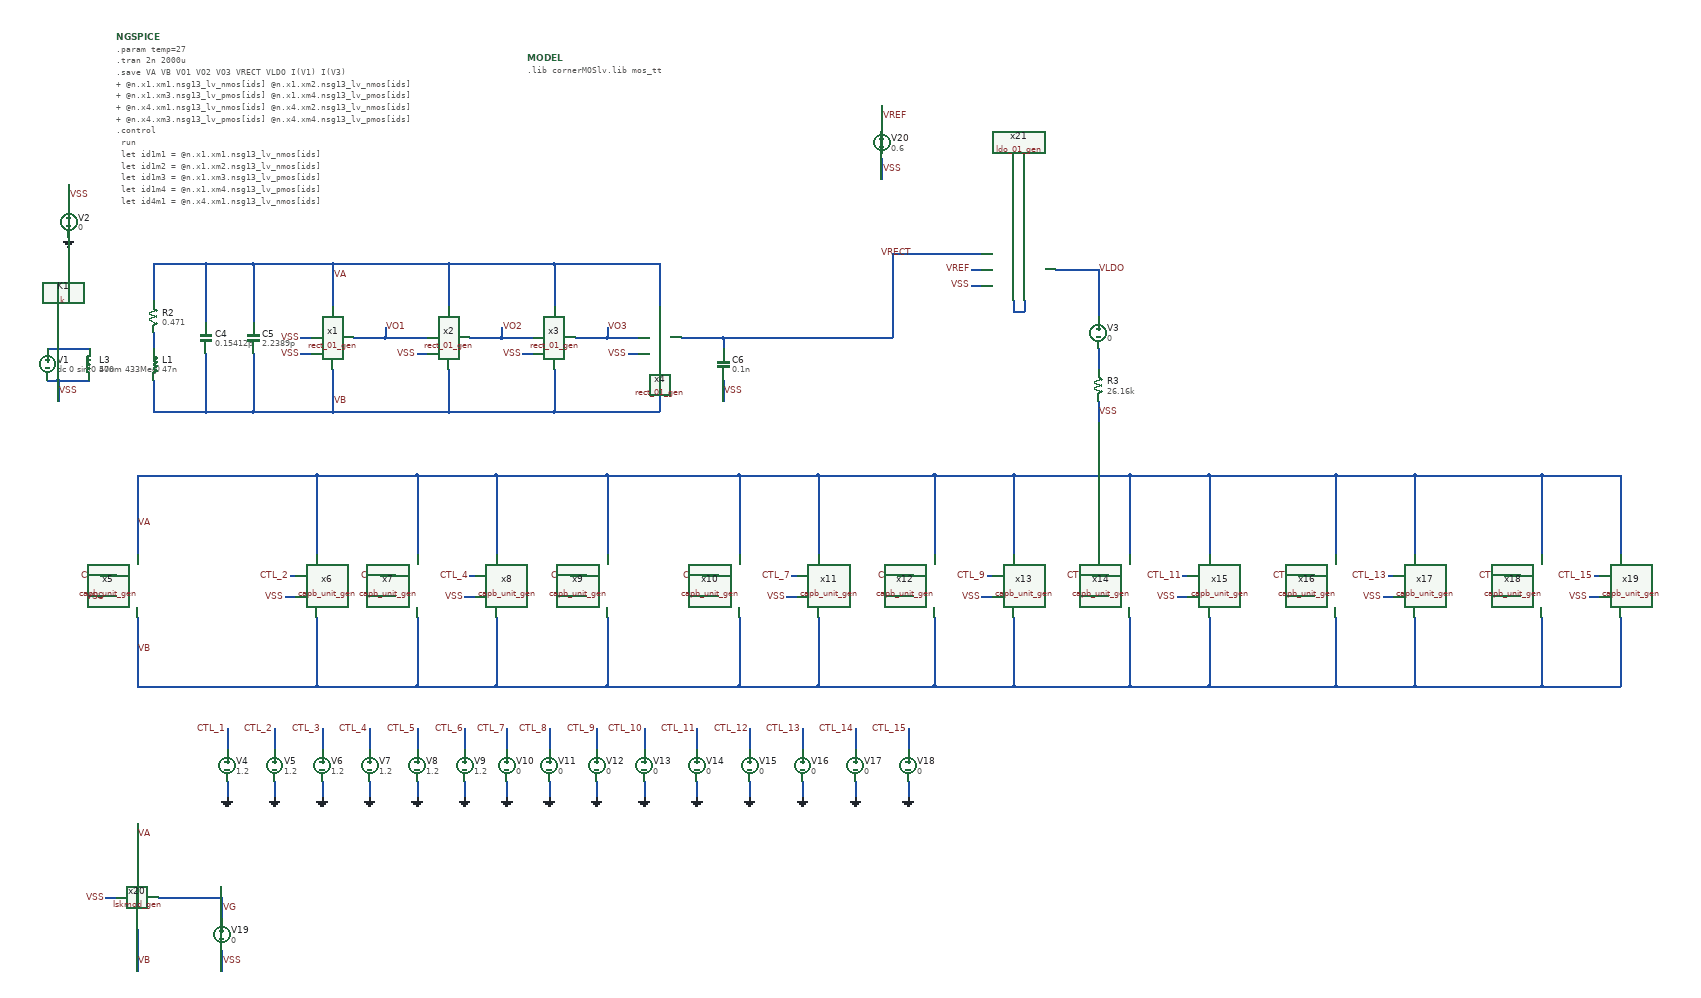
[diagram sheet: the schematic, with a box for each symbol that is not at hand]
v {xschem version=3.4.6 file_version=1.2}
G {}
K {}
V {}
S {}
E {}
N 40 -530 40 -490 {lab=VSS}
N 640 -240 720 -240 {lab=VO1}
N 480 -240 500 -240 {lab=VSS}
N 540 -380 540 -300 {lab=VA}
N 390 -380 540 -380 {lab=VA}
N 390 -100 540 -100 {lab=VB}
N 860 -240 920 -240 {lab=VO2}
N 1060 -240 1120 -240 {lab=VO3}
N 1280 -240 1280 -220 {lab=VRECT}
N 1280 -160 1280 -120 {lab=VSS}
N 1200 -240 1280 -240 {lab=VRECT}
N 1160 -180 1160 -100 {lab=VB}
N 1160 -380 1160 -300 {lab=VA}
N 960 -100 1160 -100 {lab=VB}
N 960 -380 1160 -380 {lab=VA}
N 960 -180 960 -100 {lab=VB}
N 960 -380 960 -300 {lab=VA}
N 760 -100 960 -100 {lab=VB}
N 760 -380 960 -380 {lab=VA}
N 760 -180 760 -100 {lab=VB}
N 760 -380 760 -300 {lab=VA}
N 540 -100 760 -100 {lab=VB}
N 540 -380 760 -380 {lab=VA}
N 640 -260 640 -240 {lab=VO1}
N 860 -260 860 -240 {lab=VO2}
N 800 -240 860 -240 {lab=VO2}
N 1060 -260 1060 -240 {lab=VO3}
N 1000 -240 1060 -240 {lab=VO3}
N 540 -180 540 -100 {lab=VB}
N 200 -250 200 -220 {lab=#net1}
N 200 -380 200 -310 {lab=VA}
N 300 -380 300 -270 {lab=VA}
N 390 -210 390 -100 {lab=VB}
N 390 -380 390 -270 {lab=VA}
N 580 -240 640 -240 {lab=VO1}
N 200 -160 200 -100 {lab=VB}
N 200 -380 300 -380 {lab=VA}
N 300 -380 390 -380 {lab=VA}
N 300 -210 300 -100 {lab=VB}
N 200 -100 300 -100 {lab=VB}
N 300 -100 390 -100 {lab=VB}
N 0 -220 80 -220 {lab=#net2}
N 20 -160 80 -160 {lab=VSS}
N 20 -160 20 -120 {lab=VSS}
N 0 -160 20 -160 {lab=VSS}
N 480 -210 500 -210 {lab=VSS}
N 700 -210 720 -210 {lab=VSS}
N 900 -210 920 -210 {lab=VSS}
N 1100 -210 1120 -210 {lab=VSS}
N 100 210 130 210 {lab=CTL_1}
N 460 210 470 210 {lab=CTL_2}
N 170 20 170 170 {lab=VA}
N 510 20 510 170 {lab=VA}
N 630 210 660 210 {lab=CTL_3}
N 800 210 810 210 {lab=CTL_4}
N 700 20 700 170 {lab=VA}
N 850 20 850 170 {lab=VA}
N 990 210 1020 210 {lab=CTL_5}
N 1240 210 1270 210 {lab=CTL_6}
N 1410 210 1420 210 {lab=CTL_7}
N 1610 210 1640 210 {lab=CTL_8}
N 1780 210 1790 210 {lab=CTL_9}
N 1980 210 2010 210 {lab=CTL_10}
N 2150 210 2160 210 {lab=CTL_11}
N 2200 20 2200 170 {lab=VA}
N 2370 210 2400 210 {lab=CTL_12}
N 2540 210 2550 210 {lab=CTL_13}
N 2440 20 2440 170 {lab=VA}
N 2590 20 2590 170 {lab=VA}
N 2760 210 2790 210 {lab=CTL_14}
N 2930 210 2940 210 {lab=CTL_15}
N 2830 20 2830 170 {lab=VA}
N 2980 20 2980 170 {lab=VA}
N 2830 20 2980 20 {lab=VA}
N 510 20 700 20 {lab=VA}
N 700 20 850 20 {lab=VA}
N 2200 20 2440 20 {lab=VA}
N 2440 20 2590 20 {lab=VA}
N 2590 20 2830 20 {lab=VA}
N 2830 420 2980 420 {lab=VB}
N 510 420 700 420 {lab=VB}
N 700 420 850 420 {lab=VB}
N 2050 420 2200 420 {lab=VB}
N 2200 420 2440 420 {lab=VB}
N 2440 420 2590 420 {lab=VB}
N 2590 420 2830 420 {lab=VB}
N 1830 420 2050 420 {lab=VB}
N 850 420 1060 420 {lab=VB}
N 1060 420 1310 420 {lab=VB}
N 1310 420 1460 420 {lab=VB}
N 1460 420 1680 420 {lab=VB}
N 1680 420 1830 420 {lab=VB}
N 2050 20 2200 20 {lab=VA}
N 2050 20 2050 170 {lab=VA}
N 1830 20 2050 20 {lab=VA}
N 1830 20 1830 170 {lab=VA}
N 1680 20 1830 20 {lab=VA}
N 1680 20 1680 170 {lab=VA}
N 1460 20 1680 20 {lab=VA}
N 1460 20 1460 170 {lab=VA}
N 1310 20 1460 20 {lab=VA}
N 1310 20 1310 170 {lab=VA}
N 1060 20 1310 20 {lab=VA}
N 1060 20 1060 170 {lab=VA}
N 850 20 1060 20 {lab=VA}
N 340 500 340 540 {lab=CTL_1}
N 340 600 340 630 {lab=GND}
N 430 500 430 540 {lab=CTL_2}
N 430 600 430 630 {lab=GND}
N 520 500 520 540 {lab=CTL_3}
N 520 600 520 630 {lab=GND}
N 610 500 610 540 {lab=CTL_4}
N 610 600 610 630 {lab=GND}
N 700 500 700 540 {lab=CTL_5}
N 700 600 700 630 {lab=GND}
N 790 500 790 540 {lab=CTL_6}
N 790 600 790 630 {lab=GND}
N 870 500 870 540 {lab=CTL_7}
N 870 600 870 630 {lab=GND}
N 950 500 950 540 {lab=CTL_8}
N 950 600 950 630 {lab=GND}
N 1040 500 1040 540 {lab=CTL_9}
N 1040 600 1040 630 {lab=GND}
N 1130 500 1130 540 {lab=CTL_10}
N 1130 600 1130 630 {lab=GND}
N 1230 500 1230 540 {lab=CTL_11}
N 1230 600 1230 630 {lab=GND}
N 1330 500 1330 540 {lab=CTL_12}
N 1330 600 1330 630 {lab=GND}
N 1430 500 1430 540 {lab=CTL_13}
N 1430 600 1430 630 {lab=GND}
N 1530 500 1530 540 {lab=CTL_14}
N 1530 600 1530 630 {lab=GND}
N 1630 500 1630 540 {lab=CTL_15}
N 1630 600 1630 630 {lab=GND}
N 110 250 130 250 {lab=VSS}
N 450 250 470 250 {lab=VSS}
N 640 250 660 250 {lab=VSS}
N 790 250 810 250 {lab=VSS}
N 1000 250 1020 250 {lab=VSS}
N 1250 250 1270 250 {lab=VSS}
N 1400 250 1420 250 {lab=VSS}
N 1620 250 1640 250 {lab=VSS}
N 1770 250 1790 250 {lab=VSS}
N 1990 250 2010 250 {lab=VSS}
N 2140 250 2160 250 {lab=VSS}
N 2380 250 2400 250 {lab=VSS}
N 2530 250 2550 250 {lab=VSS}
N 2770 250 2790 250 {lab=VSS}
N 2920 250 2940 250 {lab=VSS}
N 170 290 170 420 {lab=VB}
N 510 290 510 420 {lab=VB}
N 700 290 700 420 {lab=VB}
N 850 290 850 420 {lab=VB}
N 1060 290 1060 420 {lab=VB}
N 1310 290 1310 420 {lab=VB}
N 1460 290 1460 420 {lab=VB}
N 1680 290 1680 420 {lab=VB}
N 1830 290 1830 420 {lab=VB}
N 2050 290 2050 420 {lab=VB}
N 2200 290 2200 420 {lab=VB}
N 2440 290 2440 420 {lab=VB}
N 2590 290 2590 420 {lab=VB}
N 2830 290 2830 420 {lab=VB}
N 2980 290 2980 420 {lab=VB}
N 170 420 510 420 {lab=VB}
N 170 20 510 20 {lab=VA}
N 330 820 330 860 {lab=VG}
N 330 920 330 960 {lab=VSS}
N 170 680 170 760 {lab=VA}
N 170 880 170 960 {lab=VB}
N 110 820 130 820 {lab=VSS}
N 210 820 330 820 {lab=VG}
N 1580 -680 1580 -640 {lab=VREF}
N 1580 -580 1580 -540 {lab=VSS}
N 1990 -120 1990 -80 {lab=VSS}
N 1990 -370 1990 -280 {lab=VLDO}
N 1750 -370 1770 -370 {lab=VREF}
N 1910 -370 1990 -370 {lab=VLDO}
N 1850 -310 1850 -290 {lab=#net3}
N 1830 -310 1830 -290 {lab=#net3}
N 1750 -340 1770 -340 {lab=VSS}
N 1830 -290 1850 -290 {lab=#net3}
N 1280 -240 1600 -240 {lab=VRECT}
N 1600 -400 1600 -240 {lab=VRECT}
N 1600 -400 1770 -400 {lab=VRECT}
N 1990 -220 1990 -180 {lab=#net4}
C {vsource.sym} 0 -190 0 1 {name=V1 value="dc 0 sin(0 500m 433Meg)" savecurrent=false}
C {code_shown.sym} 130 -810 0 0 {name=NGSPICE only_toplevel=false value="
.param temp=27
.tran 2n 2000u
.save VA VB VO1 VO2 VO3 VRECT VLDO I(V1) I(V3)
+ @n.x1.xm1.nsg13_lv_nmos[ids] @n.x1.xm2.nsg13_lv_nmos[ids]
+ @n.x1.xm3.nsg13_lv_pmos[ids] @n.x1.xm4.nsg13_lv_pmos[ids]
+ @n.x4.xm1.nsg13_lv_nmos[ids] @n.x4.xm2.nsg13_lv_nmos[ids]
+ @n.x4.xm3.nsg13_lv_pmos[ids] @n.x4.xm4.nsg13_lv_pmos[ids]

.control
  run
  let id1m1 = @n.x1.xm1.nsg13_lv_nmos[ids]
  let id1m2 = @n.x1.xm2.nsg13_lv_nmos[ids]
  let id1m3 = @n.x1.xm3.nsg13_lv_pmos[ids]
  let id1m4 = @n.x1.xm4.nsg13_lv_pmos[ids]
  let id4m1 = @n.x4.xm1.nsg13_lv_nmos[ids]
  let id4m2 = @n.x4.xm2.nsg13_lv_nmos[ids]
  let id4m3 = @n.x4.xm3.nsg13_lv_pmos[ids]
  let id4m4 = @n.x4.xm4.nsg13_lv_pmos[ids]
  set filetype=ascii
  write tb_wpdt_g1.raw v(VA) v(VB) v(VO1) v(VO2) v(VO3) v(VRECT) v(VLDO) I(V1) I(V3) id1m1 id1m2 id1m3 id1m4 id4m1 id4m2 id4m3 id4m4
.endc
"}
C {vsource.sym} 40 -460 0 0 {name=V2 value=0 savecurrent=false}
C {gnd.sym} 40 -430 0 0 {name=l2 lab=GND}
C {lab_pin.sym} 40 -510 0 1 {name=p2 sig_type=std_logic lab=VSS}
C {code_shown.sym} 910 -770 0 0 {name=MODEL only_toplevel=false value="
.lib cornerMOSlv.lib mos_tt
"}
C {lab_pin.sym} 480 -240 0 0 {name=p9 sig_type=std_logic lab=VSS}
C {lab_pin.sym} 540 -360 0 1 {name=p1 sig_type=std_logic lab=VA}
C {lab_pin.sym} 540 -120 0 1 {name=p3 sig_type=std_logic lab=VB}
C {rect_01_gen.sym} 540 -240 0 0 {name=x1
Ls=47e-9
Rs=0.471
f_sr=1870e6
q_coil=289
f_op=433e6
Vrect=1.6
Vrfpeak=0.5
Isys=80e-6
schematic="rect_unit.py(@Ls\\,@Rs\\,@f_sr\\,@q_coil\\,@f_op\\,@Vrect\\,@Vrfpeak\\,@Isys\\)"
tclcommand="edit_file [abs_sym_path rect_unit.py]"}
C {capa.sym} 1280 -190 0 0 {name=C6
m=1
value=0.1n
footprint=1206
device="ceramic capacitor"}
C {lab_pin.sym} 1280 -140 0 1 {name=p12 sig_type=std_logic lab=VSS}
C {lab_pin.sym} 640 -260 0 1 {name=p13 sig_type=std_logic lab=VO1}
C {lab_pin.sym} 860 -260 0 1 {name=p14 sig_type=std_logic lab=VO2}
C {lab_pin.sym} 1060 -260 0 1 {name=p15 sig_type=std_logic lab=VO3}
C {vsource.sym} 1990 -250 0 0 {name=V3 value=0 savecurrent=false}
C {ind.sym} 200 -190 0 0 {name=L1
m=1
value=47n
footprint=1206
device=inductor}
C {res.sym} 200 -280 0 0 {name=R2
value=0.471
footprint=1206
device=resistor
m=1}
C {capa.sym} 300 -240 0 0 {name=C4
m=1
value=0.15412p
footprint=1206
device="ceramic capacitor"}
C {capa.sym} 390 -240 0 0 {name=C5
m=1
value=2.2389p
footprint=1206
device="ceramic capacitor"}
C {ind.sym} 80 -190 0 1 {name=L3
m=1
value=47n
footprint=1206
device=inductor}
C {lab_pin.sym} 20 -140 0 1 {name=p10 sig_type=std_logic lab=VSS}
C {k.sym} 140 -190 0 0 {name=K1 K=1 L1=L3 L2=L1}
C {lab_pin.sym} 480 -210 0 0 {name=p5 sig_type=std_logic lab=VSS}
C {lab_pin.sym} 700 -210 0 0 {name=p6 sig_type=std_logic lab=VSS}
C {lab_pin.sym} 900 -210 0 0 {name=p7 sig_type=std_logic lab=VSS}
C {lab_pin.sym} 1100 -210 0 0 {name=p11 sig_type=std_logic lab=VSS}
C {rect_01_gen.sym} 760 -240 0 0 {name=x2
Ls=47e-9
Rs=0.471
f_sr=1870e6
q_coil=289
f_op=433e6
Vrect=1.6
Vrfpeak=0.5
Isys=80e-6
schematic="rect_unit.py(@Ls\\,@Rs\\,@f_sr\\,@q_coil\\,@f_op\\,@Vrect\\,@Vrfpeak\\,@Isys\\)"
tclcommand="edit_file [abs_sym_path rect_unit.py]"}
C {rect_01_gen.sym} 960 -240 0 0 {name=x3
Ls=47e-9
Rs=0.471
f_sr=1870e6
q_coil=289
f_op=433e6
Vrect=1.6
Vrfpeak=0.5
Isys=80e-6
schematic="rect_unit.py(@Ls\\,@Rs\\,@f_sr\\,@q_coil\\,@f_op\\,@Vrect\\,@Vrfpeak\\,@Isys\\)"
tclcommand="edit_file [abs_sym_path rect_unit.py]"}
C {rect_01_gen.sym} 1160 -240 0 0 {name=x4
Ls=47e-9
Rs=0.471
f_sr=1870e6
q_coil=289
f_op=433e6
Vrect=1.6
Vrfpeak=0.5
Isys=80e-6
schematic="rect_unit.py(@Ls\\,@Rs\\,@f_sr\\,@q_coil\\,@f_op\\,@Vrect\\,@Vrfpeak\\,@Isys\\)"
tclcommand="edit_file [abs_sym_path rect_unit.py]"}
C {lab_pin.sym} 120 210 0 0 {name=p16 sig_type=std_logic lab=CTL_1}
C {lab_pin.sym} 460 210 0 0 {name=p17 sig_type=std_logic lab=CTL_2}
C {lab_pin.sym} 650 210 0 0 {name=p18 sig_type=std_logic lab=CTL_3}
C {lab_pin.sym} 800 210 0 0 {name=p19 sig_type=std_logic lab=CTL_4}
C {lab_pin.sym} 1010 210 0 0 {name=p20 sig_type=std_logic lab=CTL_5}
C {lab_pin.sym} 1260 210 0 0 {name=p21 sig_type=std_logic lab=CTL_6}
C {lab_pin.sym} 1410 210 0 0 {name=p22 sig_type=std_logic lab=CTL_7}
C {lab_pin.sym} 1630 210 0 0 {name=p23 sig_type=std_logic lab=CTL_8
}
C {lab_pin.sym} 1780 210 0 0 {name=p24 sig_type=std_logic lab=CTL_9}
C {lab_pin.sym} 2000 210 0 0 {name=p25 sig_type=std_logic lab=CTL_10}
C {lab_pin.sym} 2150 210 0 0 {name=p26 sig_type=std_logic lab=CTL_11}
C {lab_pin.sym} 2390 210 0 0 {name=p27 sig_type=std_logic lab=CTL_12}
C {lab_pin.sym} 2540 210 0 0 {name=p28 sig_type=std_logic lab=CTL_13}
C {lab_pin.sym} 2780 210 0 0 {name=p29 sig_type=std_logic lab=CTL_14}
C {lab_pin.sym} 2930 210 0 0 {name=p30 sig_type=std_logic lab=CTL_15}
C {vsource.sym} 340 570 0 0 {name=V4 value=1.2 savecurrent=false}
C {lab_pin.sym} 340 500 0 0 {name=p31 sig_type=std_logic lab=CTL_1}
C {gnd.sym} 340 630 0 0 {name=l4 lab=GND}
C {vsource.sym} 430 570 0 0 {name=V5 value=1.2 savecurrent=false}
C {lab_pin.sym} 430 500 0 0 {name=p32 sig_type=std_logic lab=CTL_2}
C {gnd.sym} 430 630 0 0 {name=l5 lab=GND}
C {vsource.sym} 520 570 0 0 {name=V6 value=1.2 savecurrent=false}
C {lab_pin.sym} 520 500 0 0 {name=p33 sig_type=std_logic lab=CTL_3}
C {gnd.sym} 520 630 0 0 {name=l7 lab=GND}
C {vsource.sym} 610 570 0 0 {name=V7 value=1.2 savecurrent=false}
C {lab_pin.sym} 610 500 0 0 {name=p34 sig_type=std_logic lab=CTL_4}
C {gnd.sym} 610 630 0 0 {name=l20 lab=GND}
C {vsource.sym} 700 570 0 0 {name=V8 value=1.2 savecurrent=false}
C {lab_pin.sym} 700 500 0 0 {name=p35 sig_type=std_logic lab=CTL_5}
C {gnd.sym} 700 630 0 0 {name=l21 lab=GND}
C {vsource.sym} 790 570 0 0 {name=V9 value=1.2 savecurrent=false}
C {lab_pin.sym} 790 500 0 0 {name=p36 sig_type=std_logic lab=CTL_6}
C {gnd.sym} 790 630 0 0 {name=l22 lab=GND}
C {vsource.sym} 870 570 0 0 {name=V10 value=0 savecurrent=false}
C {lab_pin.sym} 870 500 0 0 {name=p37 sig_type=std_logic lab=CTL_7}
C {gnd.sym} 870 630 0 0 {name=l23 lab=GND}
C {vsource.sym} 950 570 0 0 {name=V11 value=0 savecurrent=false}
C {lab_pin.sym} 950 500 0 0 {name=p38 sig_type=std_logic lab=CTL_8}
C {gnd.sym} 950 630 0 0 {name=l24 lab=GND}
C {vsource.sym} 1040 570 0 0 {name=V12 value=0 savecurrent=false}
C {lab_pin.sym} 1040 500 0 0 {name=p39 sig_type=std_logic lab=CTL_9}
C {gnd.sym} 1040 630 0 0 {name=l25 lab=GND}
C {vsource.sym} 1130 570 0 0 {name=V13 value=0 savecurrent=false}
C {lab_pin.sym} 1130 500 0 0 {name=p40 sig_type=std_logic lab=CTL_10}
C {gnd.sym} 1130 630 0 0 {name=l26 lab=GND}
C {vsource.sym} 1230 570 0 0 {name=V14 value=0 savecurrent=false}
C {lab_pin.sym} 1230 500 0 0 {name=p41 sig_type=std_logic lab=CTL_11}
C {gnd.sym} 1230 630 0 0 {name=l27 lab=GND}
C {vsource.sym} 1330 570 0 0 {name=V15 value=0 savecurrent=false}
C {lab_pin.sym} 1330 500 0 0 {name=p42 sig_type=std_logic lab=CTL_12}
C {gnd.sym} 1330 630 0 0 {name=l28 lab=GND}
C {vsource.sym} 1430 570 0 0 {name=V16 value=0 savecurrent=false}
C {lab_pin.sym} 1430 500 0 0 {name=p43 sig_type=std_logic lab=CTL_13}
C {gnd.sym} 1430 630 0 0 {name=l29 lab=GND}
C {vsource.sym} 1530 570 0 0 {name=V17 value=0 savecurrent=false}
C {lab_pin.sym} 1530 500 0 0 {name=p44 sig_type=std_logic lab=CTL_14}
C {gnd.sym} 1530 630 0 0 {name=l30 lab=GND}
C {vsource.sym} 1630 570 0 0 {name=V18 value=0 savecurrent=false}
C {lab_pin.sym} 1630 500 0 0 {name=p45 sig_type=std_logic lab=CTL_15}
C {gnd.sym} 1630 630 0 0 {name=l31 lab=GND}
C {capb_unit_gen.sym} 170 230 0 0 {name=x5
Ls=47e-9
Rs=0.471
f_sr=1870e6
q_coil=289
f_op=433e6
b=4
schematic="capb_unit.py(@Ls\\,@Rs\\,@f_sr\\,@q_coil\\,@f_op\\,@b\\)"
tclcommand="edit_file [abs_sym_path capb_unit.py]"}
C {lab_pin.sym} 110 250 0 0 {name=p46 sig_type=std_logic lab=VSS}
C {lab_pin.sym} 450 250 0 0 {name=p47 sig_type=std_logic lab=VSS}
C {lab_pin.sym} 640 250 0 0 {name=p48 sig_type=std_logic lab=VSS}
C {lab_pin.sym} 790 250 0 0 {name=p49 sig_type=std_logic lab=VSS}
C {lab_pin.sym} 1000 250 0 0 {name=p50 sig_type=std_logic lab=VSS}
C {lab_pin.sym} 1250 250 0 0 {name=p51 sig_type=std_logic lab=VSS}
C {lab_pin.sym} 1400 250 0 0 {name=p52 sig_type=std_logic lab=VSS}
C {lab_pin.sym} 1620 250 0 0 {name=p53 sig_type=std_logic lab=VSS}
C {lab_pin.sym} 1770 250 0 0 {name=p54 sig_type=std_logic lab=VSS}
C {lab_pin.sym} 1990 250 0 0 {name=p55 sig_type=std_logic lab=VSS}
C {lab_pin.sym} 2140 250 0 0 {name=p56 sig_type=std_logic lab=VSS}
C {lab_pin.sym} 2380 250 0 0 {name=p57 sig_type=std_logic lab=VSS}
C {lab_pin.sym} 2530 250 0 0 {name=p58 sig_type=std_logic lab=VSS}
C {lab_pin.sym} 2770 250 0 0 {name=p59 sig_type=std_logic lab=VSS}
C {lab_pin.sym} 2920 250 0 0 {name=p60 sig_type=std_logic lab=VSS}
C {capb_unit_gen.sym} 510 230 0 0 {name=x6
Ls=47e-9
Rs=0.471
f_sr=1870e6
q_coil=289
f_op=433e6
b=4
schematic="capb_unit.py(@Ls\\,@Rs\\,@f_sr\\,@q_coil\\,@f_op\\,@b\\)"
tclcommand="edit_file [abs_sym_path capb_unit.py]"}
C {capb_unit_gen.sym} 700 230 0 0 {name=x7
Ls=47e-9
Rs=0.471
f_sr=1870e6
q_coil=289
f_op=433e6
b=4
schematic="capb_unit.py(@Ls\\,@Rs\\,@f_sr\\,@q_coil\\,@f_op\\,@b\\)"
tclcommand="edit_file [abs_sym_path capb_unit.py]"}
C {capb_unit_gen.sym} 850 230 0 0 {name=x8
Ls=47e-9
Rs=0.471
f_sr=1870e6
q_coil=289
f_op=433e6
b=4
schematic="capb_unit.py(@Ls\\,@Rs\\,@f_sr\\,@q_coil\\,@f_op\\,@b\\)"
tclcommand="edit_file [abs_sym_path capb_unit.py]"}
C {capb_unit_gen.sym} 1060 230 0 0 {name=x9
Ls=47e-9
Rs=0.471
f_sr=1870e6
q_coil=289
f_op=433e6
b=4
schematic="capb_unit.py(@Ls\\,@Rs\\,@f_sr\\,@q_coil\\,@f_op\\,@b\\)"
tclcommand="edit_file [abs_sym_path capb_unit.py]"}
C {capb_unit_gen.sym} 1310 230 0 0 {name=x10
Ls=47e-9
Rs=0.471
f_sr=1870e6
q_coil=289
f_op=433e6
b=4
schematic="capb_unit.py(@Ls\\,@Rs\\,@f_sr\\,@q_coil\\,@f_op\\,@b\\)"
tclcommand="edit_file [abs_sym_path capb_unit.py]"}
C {capb_unit_gen.sym} 1460 230 0 0 {name=x11
Ls=47e-9
Rs=0.471
f_sr=1870e6
q_coil=289
f_op=433e6
b=4
schematic="capb_unit.py(@Ls\\,@Rs\\,@f_sr\\,@q_coil\\,@f_op\\,@b\\)"
tclcommand="edit_file [abs_sym_path capb_unit.py]"}
C {capb_unit_gen.sym} 1680 230 0 0 {name=x12
Ls=47e-9
Rs=0.471
f_sr=1870e6
q_coil=289
f_op=433e6
b=4
schematic="capb_unit.py(@Ls\\,@Rs\\,@f_sr\\,@q_coil\\,@f_op\\,@b\\)"
tclcommand="edit_file [abs_sym_path capb_unit.py]"}
C {capb_unit_gen.sym} 1830 230 0 0 {name=x13
Ls=47e-9
Rs=0.471
f_sr=1870e6
q_coil=289
f_op=433e6
b=4
schematic="capb_unit.py(@Ls\\,@Rs\\,@f_sr\\,@q_coil\\,@f_op\\,@b\\)"
tclcommand="edit_file [abs_sym_path capb_unit.py]"}
C {capb_unit_gen.sym} 2050 230 0 0 {name=x14
Ls=47e-9
Rs=0.471
f_sr=1870e6
q_coil=289
f_op=433e6
b=4
schematic="capb_unit.py(@Ls\\,@Rs\\,@f_sr\\,@q_coil\\,@f_op\\,@b\\)"
tclcommand="edit_file [abs_sym_path capb_unit.py]"}
C {capb_unit_gen.sym} 2200 230 0 0 {name=x15
Ls=47e-9
Rs=0.471
f_sr=1870e6
q_coil=289
f_op=433e6
b=4
schematic="capb_unit.py(@Ls\\,@Rs\\,@f_sr\\,@q_coil\\,@f_op\\,@b\\)"
tclcommand="edit_file [abs_sym_path capb_unit.py]"}
C {capb_unit_gen.sym} 2440 230 0 0 {name=x16
Ls=47e-9
Rs=0.471
f_sr=1870e6
q_coil=289
f_op=433e6
b=4
schematic="capb_unit.py(@Ls\\,@Rs\\,@f_sr\\,@q_coil\\,@f_op\\,@b\\)"
tclcommand="edit_file [abs_sym_path capb_unit.py]"}
C {capb_unit_gen.sym} 2590 230 0 0 {name=x17
Ls=47e-9
Rs=0.471
f_sr=1870e6
q_coil=289
f_op=433e6
b=4
schematic="capb_unit.py(@Ls\\,@Rs\\,@f_sr\\,@q_coil\\,@f_op\\,@b\\)"
tclcommand="edit_file [abs_sym_path capb_unit.py]"}
C {capb_unit_gen.sym} 2830 230 0 0 {name=x18
Ls=47e-9
Rs=0.471
f_sr=1870e6
q_coil=289
f_op=433e6
b=4
schematic="capb_unit.py(@Ls\\,@Rs\\,@f_sr\\,@q_coil\\,@f_op\\,@b\\)"
tclcommand="edit_file [abs_sym_path capb_unit.py]"}
C {capb_unit_gen.sym} 2980 230 0 0 {name=x19
Ls=47e-9
Rs=0.471
f_sr=1870e6
q_coil=289
f_op=433e6
b=4
schematic="capb_unit.py(@Ls\\,@Rs\\,@f_sr\\,@q_coil\\,@f_op\\,@b\\)"
tclcommand="edit_file [abs_sym_path capb_unit.py]"}
C {lab_pin.sym} 170 110 0 1 {name=p61 sig_type=std_logic lab=VA}
C {lab_pin.sym} 170 350 0 1 {name=p62 sig_type=std_logic lab=VB}
C {lab_pin.sym} 110 820 0 0 {name=p63 sig_type=std_logic lab=VSS}
C {vsource.sym} 330 890 0 0 {name=V19 value=0 savecurrent=false}
C {lab_pin.sym} 330 840 0 1 {name=p64 sig_type=std_logic lab=VG}
C {lab_pin.sym} 330 940 0 1 {name=p65 sig_type=std_logic lab=VSS}
C {lskmod_gen.sym} 170 820 0 0 {name=x20
Ls=47e-9
Rs=0.471
f_sr=1870e6
q_coil=289
f_op=433e6
schematic="lskmod.py(@Ls\\,@Rs\\,@f_sr\\,@q_coil\\,@f_op\\)"
tclcommand="edit_file [abs_sym_path lskmod.py]"}
C {lab_pin.sym} 170 700 0 1 {name=p66 sig_type=std_logic lab=VA}
C {lab_pin.sym} 170 940 0 1 {name=p67 sig_type=std_logic lab=VB}
C {vsource.sym} 1580 -610 0 0 {name=V20 value=0.6 savecurrent=false}
C {lab_pin.sym} 1580 -660 0 1 {name=p68 sig_type=std_logic lab=VREF}
C {lab_pin.sym} 1580 -560 0 1 {name=p69 sig_type=std_logic lab=VSS}
C {res.sym} 1990 -150 0 0 {name=R3
value=26.16k
footprint=1206
device=resistor
m=1}
C {lab_pin.sym} 1990 -100 0 1 {name=p70 sig_type=std_logic lab=VSS}
C {lab_pin.sym} 1750 -370 0 0 {name=p71 sig_type=std_logic lab=VREF}
C {lab_pin.sym} 1640 -400 1 0 {name=p72 sig_type=std_logic lab=VRECT}
C {lab_pin.sym} 1990 -370 0 1 {name=p73 sig_type=std_logic lab=VLDO}
C {ldo_01_gen.sym} 1830 -370 0 0 {name=x21
Iload=60e-6
Vldo=1.5
Vrect=1.6
Vref=0.6
schematic="ldo01.py(@Iload\\,@Vldo\\,@Vrect\\,@Vref\\)"
tclcommand="edit_file [abs_sym_path ldo01.py]"}
C {lab_pin.sym} 1750 -340 0 0 {name=p74 sig_type=std_logic lab=VSS}
